One B-rep face of a CAD part: STEP entity #52238.
In plain terms, the planar face has unit normal (0, -0.174, 0.985).
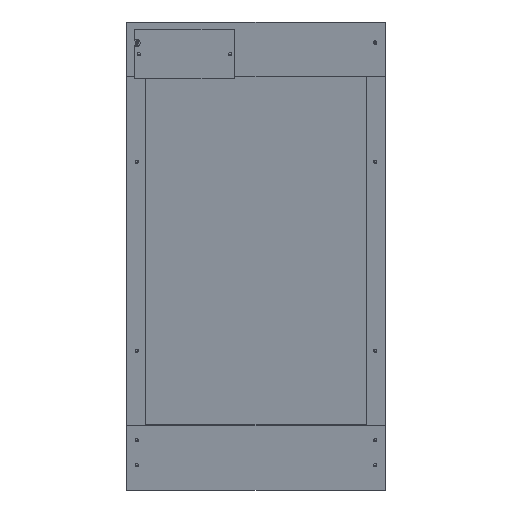
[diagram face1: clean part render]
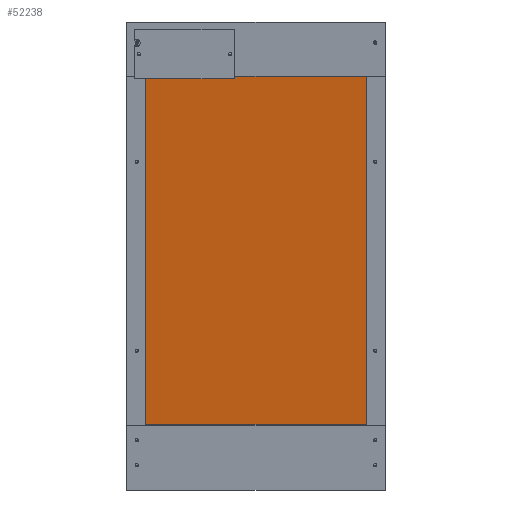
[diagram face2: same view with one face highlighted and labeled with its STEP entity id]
Its self-contained STEP definition (entity closure, numbers rounded to 3 decimals):
#52069 = PLANE('',#52070);
#52070 = AXIS2_PLACEMENT_3D('',#52071,#52072,#52073);
#52071 = CARTESIAN_POINT('',(18.1,64.,86.285));
#52072 = DIRECTION('',(-0.,1.,0.));
#52073 = DIRECTION('',(0.,0.,-1.));
#52097 = PLANE('',#52098);
#52098 = AXIS2_PLACEMENT_3D('',#52099,#52100,#52101);
#52099 = CARTESIAN_POINT('',(241.9,240.675,111.437));
#52100 = DIRECTION('',(1.,0.,0.));
#52101 = DIRECTION('',(-0.,0.,1.));
#52125 = PLANE('',#52126);
#52126 = AXIS2_PLACEMENT_3D('',#52127,#52128,#52129);
#52127 = CARTESIAN_POINT('',(18.1,417.349,136.59));
#52128 = DIRECTION('',(0.,-1.,0.));
#52129 = DIRECTION('',(0.,0.,1.));
#52151 = PLANE('',#52152);
#52152 = AXIS2_PLACEMENT_3D('',#52153,#52154,#52155);
#52153 = CARTESIAN_POINT('',(18.1,240.675,111.437));
#52154 = DIRECTION('',(1.,0.,0.));
#52155 = DIRECTION('',(-0.,0.,1.));
#52168 = VERTEX_POINT('',#52169);
#52169 = CARTESIAN_POINT('',(241.9,417.349,148.59));
#52190 = EDGE_CURVE('',#52191,#52168,#52193,.T.);
#52191 = VERTEX_POINT('',#52192);
#52192 = CARTESIAN_POINT('',(18.1,417.349,148.59));
#52193 = SURFACE_CURVE('',#52194,(#52198,#52205),.PCURVE_S1.);
#52194 = LINE('',#52195,#52196);
#52195 = CARTESIAN_POINT('',(18.1,417.349,148.59));
#52196 = VECTOR('',#52197,1.);
#52197 = DIRECTION('',(1.,0.,0.));
#52198 = PCURVE('',#52125,#52199);
#52199 = DEFINITIONAL_REPRESENTATION('',(#52200),#52204);
#52200 = LINE('',#52201,#52202);
#52201 = CARTESIAN_POINT('',(12.,0.));
#52202 = VECTOR('',#52203,1.);
#52203 = DIRECTION('',(0.,-1.));
#52204 = ( GEOMETRIC_REPRESENTATION_CONTEXT(2) 
PARAMETRIC_REPRESENTATION_CONTEXT() REPRESENTATION_CONTEXT('2D SPACE',''
  ) );
#52205 = PCURVE('',#52206,#52211);
#52206 = PLANE('',#52207);
#52207 = AXIS2_PLACEMENT_3D('',#52208,#52209,#52210);
#52208 = CARTESIAN_POINT('',(18.1,417.349,148.59));
#52209 = DIRECTION('',(0.,0.174,-0.985));
#52210 = DIRECTION('',(0.,-0.985,-0.174));
#52211 = DEFINITIONAL_REPRESENTATION('',(#52212),#52216);
#52212 = LINE('',#52213,#52214);
#52213 = CARTESIAN_POINT('',(0.,0.));
#52214 = VECTOR('',#52215,1.);
#52215 = DIRECTION('',(0.,-1.));
#52216 = ( GEOMETRIC_REPRESENTATION_CONTEXT(2) 
PARAMETRIC_REPRESENTATION_CONTEXT() REPRESENTATION_CONTEXT('2D SPACE',''
  ) );
#52238 = ADVANCED_FACE('',(#52239),#52206,.F.);
#52239 = FACE_BOUND('',#52240,.F.);
#52240 = EDGE_LOOP('',(#52241,#52242,#52265,#52288));
#52241 = ORIENTED_EDGE('',*,*,#52190,.T.);
#52242 = ORIENTED_EDGE('',*,*,#52243,.T.);
#52243 = EDGE_CURVE('',#52168,#52244,#52246,.T.);
#52244 = VERTEX_POINT('',#52245);
#52245 = CARTESIAN_POINT('',(241.9,64.,86.285));
#52246 = SURFACE_CURVE('',#52247,(#52251,#52258),.PCURVE_S1.);
#52247 = LINE('',#52248,#52249);
#52248 = CARTESIAN_POINT('',(241.9,417.349,148.59));
#52249 = VECTOR('',#52250,1.);
#52250 = DIRECTION('',(0.,-0.985,-0.174));
#52251 = PCURVE('',#52206,#52252);
#52252 = DEFINITIONAL_REPRESENTATION('',(#52253),#52257);
#52253 = LINE('',#52254,#52255);
#52254 = CARTESIAN_POINT('',(0.,-223.8));
#52255 = VECTOR('',#52256,1.);
#52256 = DIRECTION('',(1.,0.));
#52257 = ( GEOMETRIC_REPRESENTATION_CONTEXT(2) 
PARAMETRIC_REPRESENTATION_CONTEXT() REPRESENTATION_CONTEXT('2D SPACE',''
  ) );
#52258 = PCURVE('',#52097,#52259);
#52259 = DEFINITIONAL_REPRESENTATION('',(#52260),#52264);
#52260 = LINE('',#52261,#52262);
#52261 = CARTESIAN_POINT('',(37.152,-176.675));
#52262 = VECTOR('',#52263,1.);
#52263 = DIRECTION('',(-0.174,0.985));
#52264 = ( GEOMETRIC_REPRESENTATION_CONTEXT(2) 
PARAMETRIC_REPRESENTATION_CONTEXT() REPRESENTATION_CONTEXT('2D SPACE',''
  ) );
#52265 = ORIENTED_EDGE('',*,*,#52266,.F.);
#52266 = EDGE_CURVE('',#52267,#52244,#52269,.T.);
#52267 = VERTEX_POINT('',#52268);
#52268 = CARTESIAN_POINT('',(18.1,64.,86.285));
#52269 = SURFACE_CURVE('',#52270,(#52274,#52281),.PCURVE_S1.);
#52270 = LINE('',#52271,#52272);
#52271 = CARTESIAN_POINT('',(18.1,64.,86.285));
#52272 = VECTOR('',#52273,1.);
#52273 = DIRECTION('',(1.,0.,0.));
#52274 = PCURVE('',#52206,#52275);
#52275 = DEFINITIONAL_REPRESENTATION('',(#52276),#52280);
#52276 = LINE('',#52277,#52278);
#52277 = CARTESIAN_POINT('',(358.8,0.));
#52278 = VECTOR('',#52279,1.);
#52279 = DIRECTION('',(0.,-1.));
#52280 = ( GEOMETRIC_REPRESENTATION_CONTEXT(2) 
PARAMETRIC_REPRESENTATION_CONTEXT() REPRESENTATION_CONTEXT('2D SPACE',''
  ) );
#52281 = PCURVE('',#52069,#52282);
#52282 = DEFINITIONAL_REPRESENTATION('',(#52283),#52287);
#52283 = LINE('',#52284,#52285);
#52284 = CARTESIAN_POINT('',(0.,0.));
#52285 = VECTOR('',#52286,1.);
#52286 = DIRECTION('',(0.,-1.));
#52287 = ( GEOMETRIC_REPRESENTATION_CONTEXT(2) 
PARAMETRIC_REPRESENTATION_CONTEXT() REPRESENTATION_CONTEXT('2D SPACE',''
  ) );
#52288 = ORIENTED_EDGE('',*,*,#52289,.F.);
#52289 = EDGE_CURVE('',#52191,#52267,#52290,.T.);
#52290 = SURFACE_CURVE('',#52291,(#52295,#52302),.PCURVE_S1.);
#52291 = LINE('',#52292,#52293);
#52292 = CARTESIAN_POINT('',(18.1,417.349,148.59));
#52293 = VECTOR('',#52294,1.);
#52294 = DIRECTION('',(0.,-0.985,-0.174));
#52295 = PCURVE('',#52206,#52296);
#52296 = DEFINITIONAL_REPRESENTATION('',(#52297),#52301);
#52297 = LINE('',#52298,#52299);
#52298 = CARTESIAN_POINT('',(0.,0.));
#52299 = VECTOR('',#52300,1.);
#52300 = DIRECTION('',(1.,0.));
#52301 = ( GEOMETRIC_REPRESENTATION_CONTEXT(2) 
PARAMETRIC_REPRESENTATION_CONTEXT() REPRESENTATION_CONTEXT('2D SPACE',''
  ) );
#52302 = PCURVE('',#52151,#52303);
#52303 = DEFINITIONAL_REPRESENTATION('',(#52304),#52308);
#52304 = LINE('',#52305,#52306);
#52305 = CARTESIAN_POINT('',(37.152,-176.675));
#52306 = VECTOR('',#52307,1.);
#52307 = DIRECTION('',(-0.174,0.985));
#52308 = ( GEOMETRIC_REPRESENTATION_CONTEXT(2) 
PARAMETRIC_REPRESENTATION_CONTEXT() REPRESENTATION_CONTEXT('2D SPACE',''
  ) );
